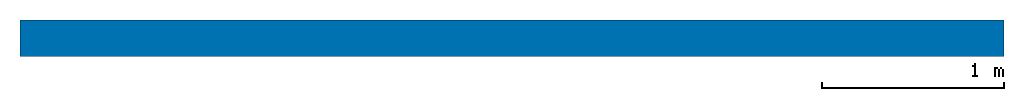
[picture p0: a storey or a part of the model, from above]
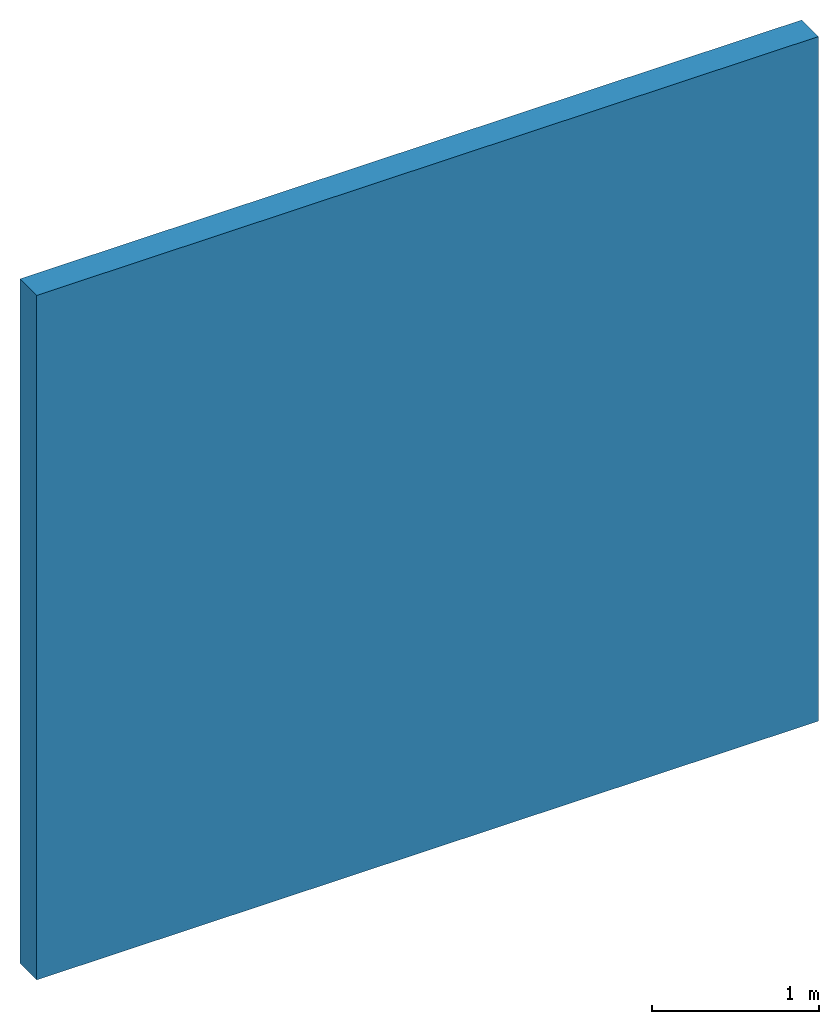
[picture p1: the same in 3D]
Properties of the parts of a building model (IFC2X3)

# File
Description: ViewDefinition [CoordinationView]
File name: example.ifc
Time: 2009-01-26T11:26:35
Author: Architect
Organization: Building Designer Office
Written by: IFC Engine DLL version 1.02 beta
Made in: IFC Engine DLL version 1.02 beta
Authorization: The authorising person

# IfcProject, Default Project
Description: Description of Default Project

# IfcSite, Default Site
Description: Description of Default Site; RefLatitude: 24, 28, 0; RefLongitude: 54, 25, 0

# IfcBuilding, Default Building
Description: Description of Default Building

# IfcBuildingStorey, Default Building Storey
In: Default Building
Description: Description of Default Building Storey; Elevation: 0 mm

# IfcWall, Wall xyz
In: Default Building Storey
Description: Description of Wall
